VERSION 5.7 ;
BUSBITCHARS "[]" ;
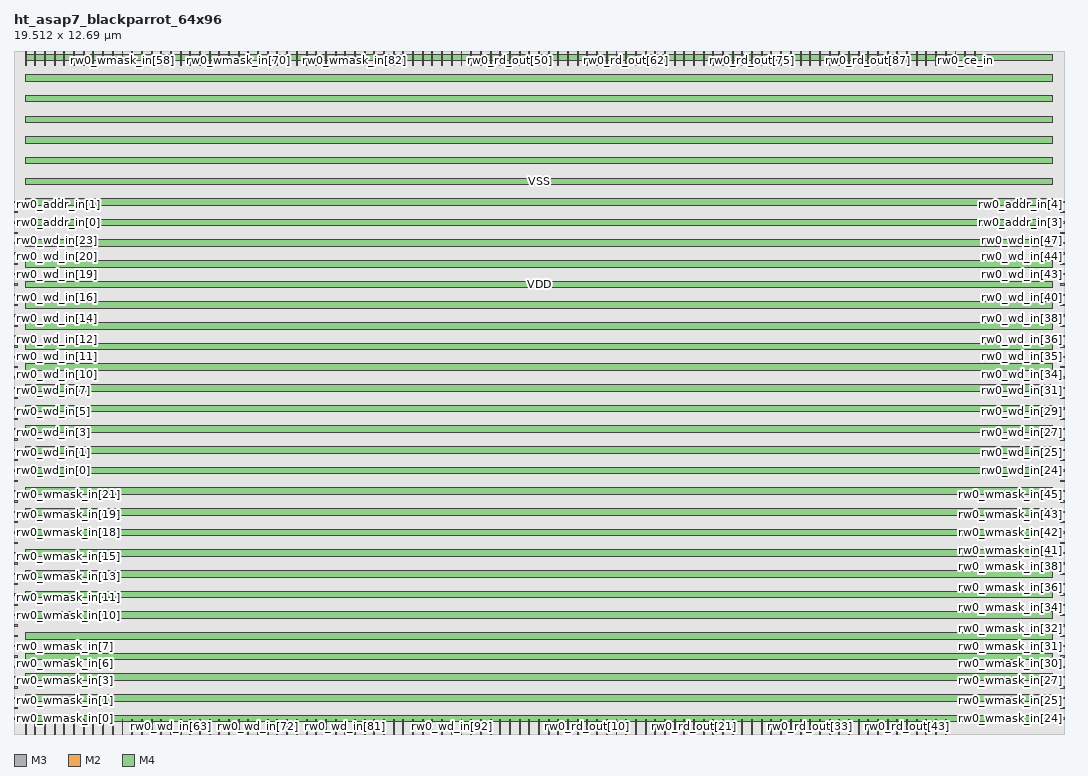
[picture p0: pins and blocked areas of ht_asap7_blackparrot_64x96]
MACRO ht_asap7_blackparrot_64x96
  FOREIGN ht_asap7_blackparrot_64x96 0 0 ;
  SYMMETRY X Y R90 ;
  SIZE 19.512 BY 12.690 ;
  CLASS BLOCK ;
  PIN rw0_wmask_in[0]
    DIRECTION INPUT ;
    USE SIGNAL ;
    SHAPE ABUTMENT ;
    PORT
      LAYER M3 ;
      RECT 0.000 0.276 0.072 0.300 ;
    END
  END rw0_wmask_in[0]
  PIN rw0_wmask_in[1]
    DIRECTION INPUT ;
    USE SIGNAL ;
    SHAPE ABUTMENT ;
    PORT
      LAYER M3 ;
      RECT 0.000 0.468 0.072 0.492 ;
    END
  END rw0_wmask_in[1]
  PIN rw0_wmask_in[2]
    DIRECTION INPUT ;
    USE SIGNAL ;
    SHAPE ABUTMENT ;
    PORT
      LAYER M3 ;
      RECT 0.000 0.660 0.072 0.684 ;
    END
  END rw0_wmask_in[2]
  PIN rw0_wmask_in[3]
    DIRECTION INPUT ;
    USE SIGNAL ;
    SHAPE ABUTMENT ;
    PORT
      LAYER M3 ;
      RECT 0.000 0.852 0.072 0.876 ;
    END
  END rw0_wmask_in[3]
  PIN rw0_wmask_in[4]
    DIRECTION INPUT ;
    USE SIGNAL ;
    SHAPE ABUTMENT ;
    PORT
      LAYER M3 ;
      RECT 0.000 1.044 0.072 1.068 ;
    END
  END rw0_wmask_in[4]
  PIN rw0_wmask_in[5]
    DIRECTION INPUT ;
    USE SIGNAL ;
    SHAPE ABUTMENT ;
    PORT
      LAYER M3 ;
      RECT 0.000 1.236 0.072 1.260 ;
    END
  END rw0_wmask_in[5]
  PIN rw0_wmask_in[6]
    DIRECTION INPUT ;
    USE SIGNAL ;
    SHAPE ABUTMENT ;
    PORT
      LAYER M3 ;
      RECT 0.000 1.428 0.072 1.452 ;
    END
  END rw0_wmask_in[6]
  PIN rw0_wmask_in[7]
    DIRECTION INPUT ;
    USE SIGNAL ;
    SHAPE ABUTMENT ;
    PORT
      LAYER M3 ;
      RECT 0.000 1.620 0.072 1.644 ;
    END
  END rw0_wmask_in[7]
  PIN rw0_wmask_in[8]
    DIRECTION INPUT ;
    USE SIGNAL ;
    SHAPE ABUTMENT ;
    PORT
      LAYER M3 ;
      RECT 0.000 1.812 0.072 1.836 ;
    END
  END rw0_wmask_in[8]
  PIN rw0_wmask_in[9]
    DIRECTION INPUT ;
    USE SIGNAL ;
    SHAPE ABUTMENT ;
    PORT
      LAYER M3 ;
      RECT 0.000 2.004 0.072 2.028 ;
    END
  END rw0_wmask_in[9]
  PIN rw0_wmask_in[10]
    DIRECTION INPUT ;
    USE SIGNAL ;
    SHAPE ABUTMENT ;
    PORT
      LAYER M3 ;
      RECT 0.000 2.196 0.072 2.220 ;
    END
  END rw0_wmask_in[10]
  PIN rw0_wmask_in[11]
    DIRECTION INPUT ;
    USE SIGNAL ;
    SHAPE ABUTMENT ;
    PORT
      LAYER M3 ;
      RECT 0.000 2.388 0.072 2.412 ;
    END
  END rw0_wmask_in[11]
  PIN rw0_wmask_in[12]
    DIRECTION INPUT ;
    USE SIGNAL ;
    SHAPE ABUTMENT ;
    PORT
      LAYER M3 ;
      RECT 0.000 2.580 0.072 2.604 ;
    END
  END rw0_wmask_in[12]
  PIN rw0_wmask_in[13]
    DIRECTION INPUT ;
    USE SIGNAL ;
    SHAPE ABUTMENT ;
    PORT
      LAYER M3 ;
      RECT 0.000 2.772 0.072 2.796 ;
    END
  END rw0_wmask_in[13]
  PIN rw0_wmask_in[14]
    DIRECTION INPUT ;
    USE SIGNAL ;
    SHAPE ABUTMENT ;
    PORT
      LAYER M3 ;
      RECT 0.000 2.964 0.072 2.988 ;
    END
  END rw0_wmask_in[14]
  PIN rw0_wmask_in[15]
    DIRECTION INPUT ;
    USE SIGNAL ;
    SHAPE ABUTMENT ;
    PORT
      LAYER M3 ;
      RECT 0.000 3.156 0.072 3.180 ;
    END
  END rw0_wmask_in[15]
  PIN rw0_wmask_in[16]
    DIRECTION INPUT ;
    USE SIGNAL ;
    SHAPE ABUTMENT ;
    PORT
      LAYER M3 ;
      RECT 0.000 3.348 0.072 3.372 ;
    END
  END rw0_wmask_in[16]
  PIN rw0_wmask_in[17]
    DIRECTION INPUT ;
    USE SIGNAL ;
    SHAPE ABUTMENT ;
    PORT
      LAYER M3 ;
      RECT 0.000 3.540 0.072 3.564 ;
    END
  END rw0_wmask_in[17]
  PIN rw0_wmask_in[18]
    DIRECTION INPUT ;
    USE SIGNAL ;
    SHAPE ABUTMENT ;
    PORT
      LAYER M3 ;
      RECT 0.000 3.732 0.072 3.756 ;
    END
  END rw0_wmask_in[18]
  PIN rw0_wmask_in[19]
    DIRECTION INPUT ;
    USE SIGNAL ;
    SHAPE ABUTMENT ;
    PORT
      LAYER M3 ;
      RECT 0.000 3.924 0.072 3.948 ;
    END
  END rw0_wmask_in[19]
  PIN rw0_wmask_in[20]
    DIRECTION INPUT ;
    USE SIGNAL ;
    SHAPE ABUTMENT ;
    PORT
      LAYER M3 ;
      RECT 0.000 4.116 0.072 4.140 ;
    END
  END rw0_wmask_in[20]
  PIN rw0_wmask_in[21]
    DIRECTION INPUT ;
    USE SIGNAL ;
    SHAPE ABUTMENT ;
    PORT
      LAYER M3 ;
      RECT 0.000 4.308 0.072 4.332 ;
    END
  END rw0_wmask_in[21]
  PIN rw0_wmask_in[22]
    DIRECTION INPUT ;
    USE SIGNAL ;
    SHAPE ABUTMENT ;
    PORT
      LAYER M3 ;
      RECT 0.000 4.500 0.072 4.524 ;
    END
  END rw0_wmask_in[22]
  PIN rw0_wmask_in[23]
    DIRECTION INPUT ;
    USE SIGNAL ;
    SHAPE ABUTMENT ;
    PORT
      LAYER M3 ;
      RECT 0.000 4.692 0.072 4.716 ;
    END
  END rw0_wmask_in[23]
  PIN rw0_wmask_in[24]
    DIRECTION INPUT ;
    USE SIGNAL ;
    SHAPE ABUTMENT ;
    PORT
      LAYER M3 ;
      RECT 19.440 0.276 19.512 0.300 ;
    END
  END rw0_wmask_in[24]
  PIN rw0_wmask_in[25]
    DIRECTION INPUT ;
    USE SIGNAL ;
    SHAPE ABUTMENT ;
    PORT
      LAYER M3 ;
      RECT 19.440 0.468 19.512 0.492 ;
    END
  END rw0_wmask_in[25]
  PIN rw0_wmask_in[26]
    DIRECTION INPUT ;
    USE SIGNAL ;
    SHAPE ABUTMENT ;
    PORT
      LAYER M3 ;
      RECT 19.440 0.660 19.512 0.684 ;
    END
  END rw0_wmask_in[26]
  PIN rw0_wmask_in[27]
    DIRECTION INPUT ;
    USE SIGNAL ;
    SHAPE ABUTMENT ;
    PORT
      LAYER M3 ;
      RECT 19.440 0.852 19.512 0.876 ;
    END
  END rw0_wmask_in[27]
  PIN rw0_wmask_in[28]
    DIRECTION INPUT ;
    USE SIGNAL ;
    SHAPE ABUTMENT ;
    PORT
      LAYER M3 ;
      RECT 19.440 1.044 19.512 1.068 ;
    END
  END rw0_wmask_in[28]
  PIN rw0_wmask_in[29]
    DIRECTION INPUT ;
    USE SIGNAL ;
    SHAPE ABUTMENT ;
    PORT
      LAYER M3 ;
      RECT 19.440 1.236 19.512 1.260 ;
    END
  END rw0_wmask_in[29]
  PIN rw0_wmask_in[30]
    DIRECTION INPUT ;
    USE SIGNAL ;
    SHAPE ABUTMENT ;
    PORT
      LAYER M3 ;
      RECT 19.440 1.428 19.512 1.452 ;
    END
  END rw0_wmask_in[30]
  PIN rw0_wmask_in[31]
    DIRECTION INPUT ;
    USE SIGNAL ;
    SHAPE ABUTMENT ;
    PORT
      LAYER M3 ;
      RECT 19.440 1.620 19.512 1.644 ;
    END
  END rw0_wmask_in[31]
  PIN rw0_wmask_in[32]
    DIRECTION INPUT ;
    USE SIGNAL ;
    SHAPE ABUTMENT ;
    PORT
      LAYER M3 ;
      RECT 19.440 1.812 19.512 1.836 ;
    END
  END rw0_wmask_in[32]
  PIN rw0_wmask_in[33]
    DIRECTION INPUT ;
    USE SIGNAL ;
    SHAPE ABUTMENT ;
    PORT
      LAYER M3 ;
      RECT 19.440 2.004 19.512 2.028 ;
    END
  END rw0_wmask_in[33]
  PIN rw0_wmask_in[34]
    DIRECTION INPUT ;
    USE SIGNAL ;
    SHAPE ABUTMENT ;
    PORT
      LAYER M3 ;
      RECT 19.440 2.196 19.512 2.220 ;
    END
  END rw0_wmask_in[34]
  PIN rw0_wmask_in[35]
    DIRECTION INPUT ;
    USE SIGNAL ;
    SHAPE ABUTMENT ;
    PORT
      LAYER M3 ;
      RECT 19.440 2.388 19.512 2.412 ;
    END
  END rw0_wmask_in[35]
  PIN rw0_wmask_in[36]
    DIRECTION INPUT ;
    USE SIGNAL ;
    SHAPE ABUTMENT ;
    PORT
      LAYER M3 ;
      RECT 19.440 2.580 19.512 2.604 ;
    END
  END rw0_wmask_in[36]
  PIN rw0_wmask_in[37]
    DIRECTION INPUT ;
    USE SIGNAL ;
    SHAPE ABUTMENT ;
    PORT
      LAYER M3 ;
      RECT 19.440 2.772 19.512 2.796 ;
    END
  END rw0_wmask_in[37]
  PIN rw0_wmask_in[38]
    DIRECTION INPUT ;
    USE SIGNAL ;
    SHAPE ABUTMENT ;
    PORT
      LAYER M3 ;
      RECT 19.440 2.964 19.512 2.988 ;
    END
  END rw0_wmask_in[38]
  PIN rw0_wmask_in[39]
    DIRECTION INPUT ;
    USE SIGNAL ;
    SHAPE ABUTMENT ;
    PORT
      LAYER M3 ;
      RECT 19.440 3.156 19.512 3.180 ;
    END
  END rw0_wmask_in[39]
  PIN rw0_wmask_in[40]
    DIRECTION INPUT ;
    USE SIGNAL ;
    SHAPE ABUTMENT ;
    PORT
      LAYER M3 ;
      RECT 19.440 3.348 19.512 3.372 ;
    END
  END rw0_wmask_in[40]
  PIN rw0_wmask_in[41]
    DIRECTION INPUT ;
    USE SIGNAL ;
    SHAPE ABUTMENT ;
    PORT
      LAYER M3 ;
      RECT 19.440 3.540 19.512 3.564 ;
    END
  END rw0_wmask_in[41]
  PIN rw0_wmask_in[42]
    DIRECTION INPUT ;
    USE SIGNAL ;
    SHAPE ABUTMENT ;
    PORT
      LAYER M3 ;
      RECT 19.440 3.732 19.512 3.756 ;
    END
  END rw0_wmask_in[42]
  PIN rw0_wmask_in[43]
    DIRECTION INPUT ;
    USE SIGNAL ;
    SHAPE ABUTMENT ;
    PORT
      LAYER M3 ;
      RECT 19.440 3.924 19.512 3.948 ;
    END
  END rw0_wmask_in[43]
  PIN rw0_wmask_in[44]
    DIRECTION INPUT ;
    USE SIGNAL ;
    SHAPE ABUTMENT ;
    PORT
      LAYER M3 ;
      RECT 19.440 4.116 19.512 4.140 ;
    END
  END rw0_wmask_in[44]
  PIN rw0_wmask_in[45]
    DIRECTION INPUT ;
    USE SIGNAL ;
    SHAPE ABUTMENT ;
    PORT
      LAYER M3 ;
      RECT 19.440 4.308 19.512 4.332 ;
    END
  END rw0_wmask_in[45]
  PIN rw0_wmask_in[46]
    DIRECTION INPUT ;
    USE SIGNAL ;
    SHAPE ABUTMENT ;
    PORT
      LAYER M3 ;
      RECT 19.440 4.500 19.512 4.524 ;
    END
  END rw0_wmask_in[46]
  PIN rw0_wmask_in[47]
    DIRECTION INPUT ;
    USE SIGNAL ;
    SHAPE ABUTMENT ;
    PORT
      LAYER M3 ;
      RECT 19.440 4.692 19.512 4.716 ;
    END
  END rw0_wmask_in[47]
  PIN rw0_wmask_in[48]
    DIRECTION INPUT ;
    USE SIGNAL ;
    SHAPE ABUTMENT ;
    PORT
      LAYER M2 ;
      RECT 0.207 12.420 0.225 12.690 ;
    END
  END rw0_wmask_in[48]
  PIN rw0_wmask_in[49]
    DIRECTION INPUT ;
    USE SIGNAL ;
    SHAPE ABUTMENT ;
    PORT
      LAYER M2 ;
      RECT 0.387 12.420 0.405 12.690 ;
    END
  END rw0_wmask_in[49]
  PIN rw0_wmask_in[50]
    DIRECTION INPUT ;
    USE SIGNAL ;
    SHAPE ABUTMENT ;
    PORT
      LAYER M2 ;
      RECT 0.567 12.420 0.585 12.690 ;
    END
  END rw0_wmask_in[50]
  PIN rw0_wmask_in[51]
    DIRECTION INPUT ;
    USE SIGNAL ;
    SHAPE ABUTMENT ;
    PORT
      LAYER M2 ;
      RECT 0.747 12.420 0.765 12.690 ;
    END
  END rw0_wmask_in[51]
  PIN rw0_wmask_in[52]
    DIRECTION INPUT ;
    USE SIGNAL ;
    SHAPE ABUTMENT ;
    PORT
      LAYER M2 ;
      RECT 0.927 12.420 0.945 12.690 ;
    END
  END rw0_wmask_in[52]
  PIN rw0_wmask_in[53]
    DIRECTION INPUT ;
    USE SIGNAL ;
    SHAPE ABUTMENT ;
    PORT
      LAYER M2 ;
      RECT 1.107 12.420 1.125 12.690 ;
    END
  END rw0_wmask_in[53]
  PIN rw0_wmask_in[54]
    DIRECTION INPUT ;
    USE SIGNAL ;
    SHAPE ABUTMENT ;
    PORT
      LAYER M2 ;
      RECT 1.287 12.420 1.305 12.690 ;
    END
  END rw0_wmask_in[54]
  PIN rw0_wmask_in[55]
    DIRECTION INPUT ;
    USE SIGNAL ;
    SHAPE ABUTMENT ;
    PORT
      LAYER M2 ;
      RECT 1.467 12.420 1.485 12.690 ;
    END
  END rw0_wmask_in[55]
  PIN rw0_wmask_in[56]
    DIRECTION INPUT ;
    USE SIGNAL ;
    SHAPE ABUTMENT ;
    PORT
      LAYER M2 ;
      RECT 1.647 12.420 1.665 12.690 ;
    END
  END rw0_wmask_in[56]
  PIN rw0_wmask_in[57]
    DIRECTION INPUT ;
    USE SIGNAL ;
    SHAPE ABUTMENT ;
    PORT
      LAYER M2 ;
      RECT 1.827 12.420 1.845 12.690 ;
    END
  END rw0_wmask_in[57]
  PIN rw0_wmask_in[58]
    DIRECTION INPUT ;
    USE SIGNAL ;
    SHAPE ABUTMENT ;
    PORT
      LAYER M2 ;
      RECT 2.007 12.420 2.025 12.690 ;
    END
  END rw0_wmask_in[58]
  PIN rw0_wmask_in[59]
    DIRECTION INPUT ;
    USE SIGNAL ;
    SHAPE ABUTMENT ;
    PORT
      LAYER M2 ;
      RECT 2.187 12.420 2.205 12.690 ;
    END
  END rw0_wmask_in[59]
  PIN rw0_wmask_in[60]
    DIRECTION INPUT ;
    USE SIGNAL ;
    SHAPE ABUTMENT ;
    PORT
      LAYER M2 ;
      RECT 2.367 12.420 2.385 12.690 ;
    END
  END rw0_wmask_in[60]
  PIN rw0_wmask_in[61]
    DIRECTION INPUT ;
    USE SIGNAL ;
    SHAPE ABUTMENT ;
    PORT
      LAYER M2 ;
      RECT 2.547 12.420 2.565 12.690 ;
    END
  END rw0_wmask_in[61]
  PIN rw0_wmask_in[62]
    DIRECTION INPUT ;
    USE SIGNAL ;
    SHAPE ABUTMENT ;
    PORT
      LAYER M2 ;
      RECT 2.727 12.420 2.745 12.690 ;
    END
  END rw0_wmask_in[62]
  PIN rw0_wmask_in[63]
    DIRECTION INPUT ;
    USE SIGNAL ;
    SHAPE ABUTMENT ;
    PORT
      LAYER M2 ;
      RECT 2.907 12.420 2.925 12.690 ;
    END
  END rw0_wmask_in[63]
  PIN rw0_wmask_in[64]
    DIRECTION INPUT ;
    USE SIGNAL ;
    SHAPE ABUTMENT ;
    PORT
      LAYER M2 ;
      RECT 3.087 12.420 3.105 12.690 ;
    END
  END rw0_wmask_in[64]
  PIN rw0_wmask_in[65]
    DIRECTION INPUT ;
    USE SIGNAL ;
    SHAPE ABUTMENT ;
    PORT
      LAYER M2 ;
      RECT 3.267 12.420 3.285 12.690 ;
    END
  END rw0_wmask_in[65]
  PIN rw0_wmask_in[66]
    DIRECTION INPUT ;
    USE SIGNAL ;
    SHAPE ABUTMENT ;
    PORT
      LAYER M2 ;
      RECT 3.447 12.420 3.465 12.690 ;
    END
  END rw0_wmask_in[66]
  PIN rw0_wmask_in[67]
    DIRECTION INPUT ;
    USE SIGNAL ;
    SHAPE ABUTMENT ;
    PORT
      LAYER M2 ;
      RECT 3.627 12.420 3.645 12.690 ;
    END
  END rw0_wmask_in[67]
  PIN rw0_wmask_in[68]
    DIRECTION INPUT ;
    USE SIGNAL ;
    SHAPE ABUTMENT ;
    PORT
      LAYER M2 ;
      RECT 3.807 12.420 3.825 12.690 ;
    END
  END rw0_wmask_in[68]
  PIN rw0_wmask_in[69]
    DIRECTION INPUT ;
    USE SIGNAL ;
    SHAPE ABUTMENT ;
    PORT
      LAYER M2 ;
      RECT 3.987 12.420 4.005 12.690 ;
    END
  END rw0_wmask_in[69]
  PIN rw0_wmask_in[70]
    DIRECTION INPUT ;
    USE SIGNAL ;
    SHAPE ABUTMENT ;
    PORT
      LAYER M2 ;
      RECT 4.167 12.420 4.185 12.690 ;
    END
  END rw0_wmask_in[70]
  PIN rw0_wmask_in[71]
    DIRECTION INPUT ;
    USE SIGNAL ;
    SHAPE ABUTMENT ;
    PORT
      LAYER M2 ;
      RECT 4.347 12.420 4.365 12.690 ;
    END
  END rw0_wmask_in[71]
  PIN rw0_wmask_in[72]
    DIRECTION INPUT ;
    USE SIGNAL ;
    SHAPE ABUTMENT ;
    PORT
      LAYER M2 ;
      RECT 4.527 12.420 4.545 12.690 ;
    END
  END rw0_wmask_in[72]
  PIN rw0_wmask_in[73]
    DIRECTION INPUT ;
    USE SIGNAL ;
    SHAPE ABUTMENT ;
    PORT
      LAYER M2 ;
      RECT 4.707 12.420 4.725 12.690 ;
    END
  END rw0_wmask_in[73]
  PIN rw0_wmask_in[74]
    DIRECTION INPUT ;
    USE SIGNAL ;
    SHAPE ABUTMENT ;
    PORT
      LAYER M2 ;
      RECT 4.887 12.420 4.905 12.690 ;
    END
  END rw0_wmask_in[74]
  PIN rw0_wmask_in[75]
    DIRECTION INPUT ;
    USE SIGNAL ;
    SHAPE ABUTMENT ;
    PORT
      LAYER M2 ;
      RECT 5.067 12.420 5.085 12.690 ;
    END
  END rw0_wmask_in[75]
  PIN rw0_wmask_in[76]
    DIRECTION INPUT ;
    USE SIGNAL ;
    SHAPE ABUTMENT ;
    PORT
      LAYER M2 ;
      RECT 5.247 12.420 5.265 12.690 ;
    END
  END rw0_wmask_in[76]
  PIN rw0_wmask_in[77]
    DIRECTION INPUT ;
    USE SIGNAL ;
    SHAPE ABUTMENT ;
    PORT
      LAYER M2 ;
      RECT 5.427 12.420 5.445 12.690 ;
    END
  END rw0_wmask_in[77]
  PIN rw0_wmask_in[78]
    DIRECTION INPUT ;
    USE SIGNAL ;
    SHAPE ABUTMENT ;
    PORT
      LAYER M2 ;
      RECT 5.607 12.420 5.625 12.690 ;
    END
  END rw0_wmask_in[78]
  PIN rw0_wmask_in[79]
    DIRECTION INPUT ;
    USE SIGNAL ;
    SHAPE ABUTMENT ;
    PORT
      LAYER M2 ;
      RECT 5.787 12.420 5.805 12.690 ;
    END
  END rw0_wmask_in[79]
  PIN rw0_wmask_in[80]
    DIRECTION INPUT ;
    USE SIGNAL ;
    SHAPE ABUTMENT ;
    PORT
      LAYER M2 ;
      RECT 5.967 12.420 5.985 12.690 ;
    END
  END rw0_wmask_in[80]
  PIN rw0_wmask_in[81]
    DIRECTION INPUT ;
    USE SIGNAL ;
    SHAPE ABUTMENT ;
    PORT
      LAYER M2 ;
      RECT 6.147 12.420 6.165 12.690 ;
    END
  END rw0_wmask_in[81]
  PIN rw0_wmask_in[82]
    DIRECTION INPUT ;
    USE SIGNAL ;
    SHAPE ABUTMENT ;
    PORT
      LAYER M2 ;
      RECT 6.327 12.420 6.345 12.690 ;
    END
  END rw0_wmask_in[82]
  PIN rw0_wmask_in[83]
    DIRECTION INPUT ;
    USE SIGNAL ;
    SHAPE ABUTMENT ;
    PORT
      LAYER M2 ;
      RECT 6.507 12.420 6.525 12.690 ;
    END
  END rw0_wmask_in[83]
  PIN rw0_wmask_in[84]
    DIRECTION INPUT ;
    USE SIGNAL ;
    SHAPE ABUTMENT ;
    PORT
      LAYER M2 ;
      RECT 6.687 12.420 6.705 12.690 ;
    END
  END rw0_wmask_in[84]
  PIN rw0_wmask_in[85]
    DIRECTION INPUT ;
    USE SIGNAL ;
    SHAPE ABUTMENT ;
    PORT
      LAYER M2 ;
      RECT 6.867 12.420 6.885 12.690 ;
    END
  END rw0_wmask_in[85]
  PIN rw0_wmask_in[86]
    DIRECTION INPUT ;
    USE SIGNAL ;
    SHAPE ABUTMENT ;
    PORT
      LAYER M2 ;
      RECT 7.047 12.420 7.065 12.690 ;
    END
  END rw0_wmask_in[86]
  PIN rw0_wmask_in[87]
    DIRECTION INPUT ;
    USE SIGNAL ;
    SHAPE ABUTMENT ;
    PORT
      LAYER M2 ;
      RECT 7.227 12.420 7.245 12.690 ;
    END
  END rw0_wmask_in[87]
  PIN rw0_wmask_in[88]
    DIRECTION INPUT ;
    USE SIGNAL ;
    SHAPE ABUTMENT ;
    PORT
      LAYER M2 ;
      RECT 7.407 12.420 7.425 12.690 ;
    END
  END rw0_wmask_in[88]
  PIN rw0_wmask_in[89]
    DIRECTION INPUT ;
    USE SIGNAL ;
    SHAPE ABUTMENT ;
    PORT
      LAYER M2 ;
      RECT 7.587 12.420 7.605 12.690 ;
    END
  END rw0_wmask_in[89]
  PIN rw0_wmask_in[90]
    DIRECTION INPUT ;
    USE SIGNAL ;
    SHAPE ABUTMENT ;
    PORT
      LAYER M2 ;
      RECT 7.767 12.420 7.785 12.690 ;
    END
  END rw0_wmask_in[90]
  PIN rw0_wmask_in[91]
    DIRECTION INPUT ;
    USE SIGNAL ;
    SHAPE ABUTMENT ;
    PORT
      LAYER M2 ;
      RECT 7.947 12.420 7.965 12.690 ;
    END
  END rw0_wmask_in[91]
  PIN rw0_wmask_in[92]
    DIRECTION INPUT ;
    USE SIGNAL ;
    SHAPE ABUTMENT ;
    PORT
      LAYER M2 ;
      RECT 8.127 12.420 8.145 12.690 ;
    END
  END rw0_wmask_in[92]
  PIN rw0_wmask_in[93]
    DIRECTION INPUT ;
    USE SIGNAL ;
    SHAPE ABUTMENT ;
    PORT
      LAYER M2 ;
      RECT 8.307 12.420 8.325 12.690 ;
    END
  END rw0_wmask_in[93]
  PIN rw0_wmask_in[94]
    DIRECTION INPUT ;
    USE SIGNAL ;
    SHAPE ABUTMENT ;
    PORT
      LAYER M2 ;
      RECT 8.487 12.420 8.505 12.690 ;
    END
  END rw0_wmask_in[94]
  PIN rw0_wmask_in[95]
    DIRECTION INPUT ;
    USE SIGNAL ;
    SHAPE ABUTMENT ;
    PORT
      LAYER M2 ;
      RECT 8.667 12.420 8.685 12.690 ;
    END
  END rw0_wmask_in[95]
  PIN rw0_wd_in[0]
    DIRECTION INPUT ;
    USE SIGNAL ;
    SHAPE ABUTMENT ;
    PORT
      LAYER M3 ;
      RECT 0.000 4.884 0.072 4.908 ;
    END
  END rw0_wd_in[0]
  PIN rw0_wd_in[1]
    DIRECTION INPUT ;
    USE SIGNAL ;
    SHAPE ABUTMENT ;
    PORT
      LAYER M3 ;
      RECT 0.000 5.076 0.072 5.100 ;
    END
  END rw0_wd_in[1]
  PIN rw0_wd_in[2]
    DIRECTION INPUT ;
    USE SIGNAL ;
    SHAPE ABUTMENT ;
    PORT
      LAYER M3 ;
      RECT 0.000 5.268 0.072 5.292 ;
    END
  END rw0_wd_in[2]
  PIN rw0_wd_in[3]
    DIRECTION INPUT ;
    USE SIGNAL ;
    SHAPE ABUTMENT ;
    PORT
      LAYER M3 ;
      RECT 0.000 5.460 0.072 5.484 ;
    END
  END rw0_wd_in[3]
  PIN rw0_wd_in[4]
    DIRECTION INPUT ;
    USE SIGNAL ;
    SHAPE ABUTMENT ;
    PORT
      LAYER M3 ;
      RECT 0.000 5.652 0.072 5.676 ;
    END
  END rw0_wd_in[4]
  PIN rw0_wd_in[5]
    DIRECTION INPUT ;
    USE SIGNAL ;
    SHAPE ABUTMENT ;
    PORT
      LAYER M3 ;
      RECT 0.000 5.844 0.072 5.868 ;
    END
  END rw0_wd_in[5]
  PIN rw0_wd_in[6]
    DIRECTION INPUT ;
    USE SIGNAL ;
    SHAPE ABUTMENT ;
    PORT
      LAYER M3 ;
      RECT 0.000 6.036 0.072 6.060 ;
    END
  END rw0_wd_in[6]
  PIN rw0_wd_in[7]
    DIRECTION INPUT ;
    USE SIGNAL ;
    SHAPE ABUTMENT ;
    PORT
      LAYER M3 ;
      RECT 0.000 6.228 0.072 6.252 ;
    END
  END rw0_wd_in[7]
  PIN rw0_wd_in[8]
    DIRECTION INPUT ;
    USE SIGNAL ;
    SHAPE ABUTMENT ;
    PORT
      LAYER M3 ;
      RECT 0.000 6.420 0.072 6.444 ;
    END
  END rw0_wd_in[8]
  PIN rw0_wd_in[9]
    DIRECTION INPUT ;
    USE SIGNAL ;
    SHAPE ABUTMENT ;
    PORT
      LAYER M3 ;
      RECT 0.000 6.612 0.072 6.636 ;
    END
  END rw0_wd_in[9]
  PIN rw0_wd_in[10]
    DIRECTION INPUT ;
    USE SIGNAL ;
    SHAPE ABUTMENT ;
    PORT
      LAYER M3 ;
      RECT 0.000 6.804 0.072 6.828 ;
    END
  END rw0_wd_in[10]
  PIN rw0_wd_in[11]
    DIRECTION INPUT ;
    USE SIGNAL ;
    SHAPE ABUTMENT ;
    PORT
      LAYER M3 ;
      RECT 0.000 6.996 0.072 7.020 ;
    END
  END rw0_wd_in[11]
  PIN rw0_wd_in[12]
    DIRECTION INPUT ;
    USE SIGNAL ;
    SHAPE ABUTMENT ;
    PORT
      LAYER M3 ;
      RECT 0.000 7.188 0.072 7.212 ;
    END
  END rw0_wd_in[12]
  PIN rw0_wd_in[13]
    DIRECTION INPUT ;
    USE SIGNAL ;
    SHAPE ABUTMENT ;
    PORT
      LAYER M3 ;
      RECT 0.000 7.380 0.072 7.404 ;
    END
  END rw0_wd_in[13]
  PIN rw0_wd_in[14]
    DIRECTION INPUT ;
    USE SIGNAL ;
    SHAPE ABUTMENT ;
    PORT
      LAYER M3 ;
      RECT 0.000 7.572 0.072 7.596 ;
    END
  END rw0_wd_in[14]
  PIN rw0_wd_in[15]
    DIRECTION INPUT ;
    USE SIGNAL ;
    SHAPE ABUTMENT ;
    PORT
      LAYER M3 ;
      RECT 0.000 7.764 0.072 7.788 ;
    END
  END rw0_wd_in[15]
  PIN rw0_wd_in[16]
    DIRECTION INPUT ;
    USE SIGNAL ;
    SHAPE ABUTMENT ;
    PORT
      LAYER M3 ;
      RECT 0.000 7.956 0.072 7.980 ;
    END
  END rw0_wd_in[16]
  PIN rw0_wd_in[17]
    DIRECTION INPUT ;
    USE SIGNAL ;
    SHAPE ABUTMENT ;
    PORT
      LAYER M3 ;
      RECT 0.000 8.148 0.072 8.172 ;
    END
  END rw0_wd_in[17]
  PIN rw0_wd_in[18]
    DIRECTION INPUT ;
    USE SIGNAL ;
    SHAPE ABUTMENT ;
    PORT
      LAYER M3 ;
      RECT 0.000 8.340 0.072 8.364 ;
    END
  END rw0_wd_in[18]
  PIN rw0_wd_in[19]
    DIRECTION INPUT ;
    USE SIGNAL ;
    SHAPE ABUTMENT ;
    PORT
      LAYER M3 ;
      RECT 0.000 8.532 0.072 8.556 ;
    END
  END rw0_wd_in[19]
  PIN rw0_wd_in[20]
    DIRECTION INPUT ;
    USE SIGNAL ;
    SHAPE ABUTMENT ;
    PORT
      LAYER M3 ;
      RECT 0.000 8.724 0.072 8.748 ;
    END
  END rw0_wd_in[20]
  PIN rw0_wd_in[21]
    DIRECTION INPUT ;
    USE SIGNAL ;
    SHAPE ABUTMENT ;
    PORT
      LAYER M3 ;
      RECT 0.000 8.916 0.072 8.940 ;
    END
  END rw0_wd_in[21]
  PIN rw0_wd_in[22]
    DIRECTION INPUT ;
    USE SIGNAL ;
    SHAPE ABUTMENT ;
    PORT
      LAYER M3 ;
      RECT 0.000 9.108 0.072 9.132 ;
    END
  END rw0_wd_in[22]
  PIN rw0_wd_in[23]
    DIRECTION INPUT ;
    USE SIGNAL ;
    SHAPE ABUTMENT ;
    PORT
      LAYER M3 ;
      RECT 0.000 9.300 0.072 9.324 ;
    END
  END rw0_wd_in[23]
  PIN rw0_wd_in[24]
    DIRECTION INPUT ;
    USE SIGNAL ;
    SHAPE ABUTMENT ;
    PORT
      LAYER M3 ;
      RECT 19.440 4.884 19.512 4.908 ;
    END
  END rw0_wd_in[24]
  PIN rw0_wd_in[25]
    DIRECTION INPUT ;
    USE SIGNAL ;
    SHAPE ABUTMENT ;
    PORT
      LAYER M3 ;
      RECT 19.440 5.076 19.512 5.100 ;
    END
  END rw0_wd_in[25]
  PIN rw0_wd_in[26]
    DIRECTION INPUT ;
    USE SIGNAL ;
    SHAPE ABUTMENT ;
    PORT
      LAYER M3 ;
      RECT 19.440 5.268 19.512 5.292 ;
    END
  END rw0_wd_in[26]
  PIN rw0_wd_in[27]
    DIRECTION INPUT ;
    USE SIGNAL ;
    SHAPE ABUTMENT ;
    PORT
      LAYER M3 ;
      RECT 19.440 5.460 19.512 5.484 ;
    END
  END rw0_wd_in[27]
  PIN rw0_wd_in[28]
    DIRECTION INPUT ;
    USE SIGNAL ;
    SHAPE ABUTMENT ;
    PORT
      LAYER M3 ;
      RECT 19.440 5.652 19.512 5.676 ;
    END
  END rw0_wd_in[28]
  PIN rw0_wd_in[29]
    DIRECTION INPUT ;
    USE SIGNAL ;
    SHAPE ABUTMENT ;
    PORT
      LAYER M3 ;
      RECT 19.440 5.844 19.512 5.868 ;
    END
  END rw0_wd_in[29]
  PIN rw0_wd_in[30]
    DIRECTION INPUT ;
    USE SIGNAL ;
    SHAPE ABUTMENT ;
    PORT
      LAYER M3 ;
      RECT 19.440 6.036 19.512 6.060 ;
    END
  END rw0_wd_in[30]
  PIN rw0_wd_in[31]
    DIRECTION INPUT ;
    USE SIGNAL ;
    SHAPE ABUTMENT ;
    PORT
      LAYER M3 ;
      RECT 19.440 6.228 19.512 6.252 ;
    END
  END rw0_wd_in[31]
  PIN rw0_wd_in[32]
    DIRECTION INPUT ;
    USE SIGNAL ;
    SHAPE ABUTMENT ;
    PORT
      LAYER M3 ;
      RECT 19.440 6.420 19.512 6.444 ;
    END
  END rw0_wd_in[32]
  PIN rw0_wd_in[33]
    DIRECTION INPUT ;
    USE SIGNAL ;
    SHAPE ABUTMENT ;
    PORT
      LAYER M3 ;
      RECT 19.440 6.612 19.512 6.636 ;
    END
  END rw0_wd_in[33]
  PIN rw0_wd_in[34]
    DIRECTION INPUT ;
    USE SIGNAL ;
    SHAPE ABUTMENT ;
    PORT
      LAYER M3 ;
      RECT 19.440 6.804 19.512 6.828 ;
    END
  END rw0_wd_in[34]
  PIN rw0_wd_in[35]
    DIRECTION INPUT ;
    USE SIGNAL ;
    SHAPE ABUTMENT ;
    PORT
      LAYER M3 ;
      RECT 19.440 6.996 19.512 7.020 ;
    END
  END rw0_wd_in[35]
  PIN rw0_wd_in[36]
    DIRECTION INPUT ;
    USE SIGNAL ;
    SHAPE ABUTMENT ;
    PORT
      LAYER M3 ;
      RECT 19.440 7.188 19.512 7.212 ;
    END
  END rw0_wd_in[36]
  PIN rw0_wd_in[37]
    DIRECTION INPUT ;
    USE SIGNAL ;
    SHAPE ABUTMENT ;
    PORT
      LAYER M3 ;
      RECT 19.440 7.380 19.512 7.404 ;
    END
  END rw0_wd_in[37]
  PIN rw0_wd_in[38]
    DIRECTION INPUT ;
    USE SIGNAL ;
    SHAPE ABUTMENT ;
    PORT
      LAYER M3 ;
      RECT 19.440 7.572 19.512 7.596 ;
    END
  END rw0_wd_in[38]
  PIN rw0_wd_in[39]
    DIRECTION INPUT ;
    USE SIGNAL ;
    SHAPE ABUTMENT ;
    PORT
      LAYER M3 ;
      RECT 19.440 7.764 19.512 7.788 ;
    END
  END rw0_wd_in[39]
  PIN rw0_wd_in[40]
    DIRECTION INPUT ;
    USE SIGNAL ;
    SHAPE ABUTMENT ;
    PORT
      LAYER M3 ;
      RECT 19.440 7.956 19.512 7.980 ;
    END
  END rw0_wd_in[40]
  PIN rw0_wd_in[41]
    DIRECTION INPUT ;
    USE SIGNAL ;
    SHAPE ABUTMENT ;
    PORT
      LAYER M3 ;
      RECT 19.440 8.148 19.512 8.172 ;
    END
  END rw0_wd_in[41]
  PIN rw0_wd_in[42]
    DIRECTION INPUT ;
    USE SIGNAL ;
    SHAPE ABUTMENT ;
    PORT
      LAYER M3 ;
      RECT 19.440 8.340 19.512 8.364 ;
    END
  END rw0_wd_in[42]
  PIN rw0_wd_in[43]
    DIRECTION INPUT ;
    USE SIGNAL ;
    SHAPE ABUTMENT ;
    PORT
      LAYER M3 ;
      RECT 19.440 8.532 19.512 8.556 ;
    END
  END rw0_wd_in[43]
  PIN rw0_wd_in[44]
    DIRECTION INPUT ;
    USE SIGNAL ;
    SHAPE ABUTMENT ;
    PORT
      LAYER M3 ;
      RECT 19.440 8.724 19.512 8.748 ;
    END
  END rw0_wd_in[44]
  PIN rw0_wd_in[45]
    DIRECTION INPUT ;
    USE SIGNAL ;
    SHAPE ABUTMENT ;
    PORT
      LAYER M3 ;
      RECT 19.440 8.916 19.512 8.940 ;
    END
  END rw0_wd_in[45]
  PIN rw0_wd_in[46]
    DIRECTION INPUT ;
    USE SIGNAL ;
    SHAPE ABUTMENT ;
    PORT
      LAYER M3 ;
      RECT 19.440 9.108 19.512 9.132 ;
    END
  END rw0_wd_in[46]
  PIN rw0_wd_in[47]
    DIRECTION INPUT ;
    USE SIGNAL ;
    SHAPE ABUTMENT ;
    PORT
      LAYER M3 ;
      RECT 19.440 9.300 19.512 9.324 ;
    END
  END rw0_wd_in[47]
  PIN rw0_wd_in[48]
    DIRECTION INPUT ;
    USE SIGNAL ;
    SHAPE ABUTMENT ;
    PORT
      LAYER M2 ;
      RECT 0.207 0.000 0.225 0.270 ;
    END
  END rw0_wd_in[48]
  PIN rw0_wd_in[49]
    DIRECTION INPUT ;
    USE SIGNAL ;
    SHAPE ABUTMENT ;
    PORT
      LAYER M2 ;
      RECT 0.387 0.000 0.405 0.270 ;
    END
  END rw0_wd_in[49]
  PIN rw0_wd_in[50]
    DIRECTION INPUT ;
    USE SIGNAL ;
    SHAPE ABUTMENT ;
    PORT
      LAYER M2 ;
      RECT 0.567 0.000 0.585 0.270 ;
    END
  END rw0_wd_in[50]
  PIN rw0_wd_in[51]
    DIRECTION INPUT ;
    USE SIGNAL ;
    SHAPE ABUTMENT ;
    PORT
      LAYER M2 ;
      RECT 0.747 0.000 0.765 0.270 ;
    END
  END rw0_wd_in[51]
  PIN rw0_wd_in[52]
    DIRECTION INPUT ;
    USE SIGNAL ;
    SHAPE ABUTMENT ;
    PORT
      LAYER M2 ;
      RECT 0.927 0.000 0.945 0.270 ;
    END
  END rw0_wd_in[52]
  PIN rw0_wd_in[53]
    DIRECTION INPUT ;
    USE SIGNAL ;
    SHAPE ABUTMENT ;
    PORT
      LAYER M2 ;
      RECT 1.107 0.000 1.125 0.270 ;
    END
  END rw0_wd_in[53]
  PIN rw0_wd_in[54]
    DIRECTION INPUT ;
    USE SIGNAL ;
    SHAPE ABUTMENT ;
    PORT
      LAYER M2 ;
      RECT 1.287 0.000 1.305 0.270 ;
    END
  END rw0_wd_in[54]
  PIN rw0_wd_in[55]
    DIRECTION INPUT ;
    USE SIGNAL ;
    SHAPE ABUTMENT ;
    PORT
      LAYER M2 ;
      RECT 1.467 0.000 1.485 0.270 ;
    END
  END rw0_wd_in[55]
  PIN rw0_wd_in[56]
    DIRECTION INPUT ;
    USE SIGNAL ;
    SHAPE ABUTMENT ;
    PORT
      LAYER M2 ;
      RECT 1.647 0.000 1.665 0.270 ;
    END
  END rw0_wd_in[56]
  PIN rw0_wd_in[57]
    DIRECTION INPUT ;
    USE SIGNAL ;
    SHAPE ABUTMENT ;
    PORT
      LAYER M2 ;
      RECT 1.827 0.000 1.845 0.270 ;
    END
  END rw0_wd_in[57]
  PIN rw0_wd_in[58]
    DIRECTION INPUT ;
    USE SIGNAL ;
    SHAPE ABUTMENT ;
    PORT
      LAYER M2 ;
      RECT 2.007 0.000 2.025 0.270 ;
    END
  END rw0_wd_in[58]
  PIN rw0_wd_in[59]
    DIRECTION INPUT ;
    USE SIGNAL ;
    SHAPE ABUTMENT ;
    PORT
      LAYER M2 ;
      RECT 2.187 0.000 2.205 0.270 ;
    END
  END rw0_wd_in[59]
  PIN rw0_wd_in[60]
    DIRECTION INPUT ;
    USE SIGNAL ;
    SHAPE ABUTMENT ;
    PORT
      LAYER M2 ;
      RECT 2.367 0.000 2.385 0.270 ;
    END
  END rw0_wd_in[60]
  PIN rw0_wd_in[61]
    DIRECTION INPUT ;
    USE SIGNAL ;
    SHAPE ABUTMENT ;
    PORT
      LAYER M2 ;
      RECT 2.547 0.000 2.565 0.270 ;
    END
  END rw0_wd_in[61]
  PIN rw0_wd_in[62]
    DIRECTION INPUT ;
    USE SIGNAL ;
    SHAPE ABUTMENT ;
    PORT
      LAYER M2 ;
      RECT 2.727 0.000 2.745 0.270 ;
    END
  END rw0_wd_in[62]
  PIN rw0_wd_in[63]
    DIRECTION INPUT ;
    USE SIGNAL ;
    SHAPE ABUTMENT ;
    PORT
      LAYER M2 ;
      RECT 2.907 0.000 2.925 0.270 ;
    END
  END rw0_wd_in[63]
  PIN rw0_wd_in[64]
    DIRECTION INPUT ;
    USE SIGNAL ;
    SHAPE ABUTMENT ;
    PORT
      LAYER M2 ;
      RECT 3.087 0.000 3.105 0.270 ;
    END
  END rw0_wd_in[64]
  PIN rw0_wd_in[65]
    DIRECTION INPUT ;
    USE SIGNAL ;
    SHAPE ABUTMENT ;
    PORT
      LAYER M2 ;
      RECT 3.267 0.000 3.285 0.270 ;
    END
  END rw0_wd_in[65]
  PIN rw0_wd_in[66]
    DIRECTION INPUT ;
    USE SIGNAL ;
    SHAPE ABUTMENT ;
    PORT
      LAYER M2 ;
      RECT 3.447 0.000 3.465 0.270 ;
    END
  END rw0_wd_in[66]
  PIN rw0_wd_in[67]
    DIRECTION INPUT ;
    USE SIGNAL ;
    SHAPE ABUTMENT ;
    PORT
      LAYER M2 ;
      RECT 3.627 0.000 3.645 0.270 ;
    END
  END rw0_wd_in[67]
  PIN rw0_wd_in[68]
    DIRECTION INPUT ;
    USE SIGNAL ;
    SHAPE ABUTMENT ;
    PORT
      LAYER M2 ;
      RECT 3.807 0.000 3.825 0.270 ;
    END
  END rw0_wd_in[68]
  PIN rw0_wd_in[69]
    DIRECTION INPUT ;
    USE SIGNAL ;
    SHAPE ABUTMENT ;
    PORT
      LAYER M2 ;
      RECT 3.987 0.000 4.005 0.270 ;
    END
  END rw0_wd_in[69]
  PIN rw0_wd_in[70]
    DIRECTION INPUT ;
    USE SIGNAL ;
    SHAPE ABUTMENT ;
    PORT
      LAYER M2 ;
      RECT 4.167 0.000 4.185 0.270 ;
    END
  END rw0_wd_in[70]
  PIN rw0_wd_in[71]
    DIRECTION INPUT ;
    USE SIGNAL ;
    SHAPE ABUTMENT ;
    PORT
      LAYER M2 ;
      RECT 4.347 0.000 4.365 0.270 ;
    END
  END rw0_wd_in[71]
  PIN rw0_wd_in[72]
    DIRECTION INPUT ;
    USE SIGNAL ;
    SHAPE ABUTMENT ;
    PORT
      LAYER M2 ;
      RECT 4.527 0.000 4.545 0.270 ;
    END
  END rw0_wd_in[72]
  PIN rw0_wd_in[73]
    DIRECTION INPUT ;
    USE SIGNAL ;
    SHAPE ABUTMENT ;
    PORT
      LAYER M2 ;
      RECT 4.707 0.000 4.725 0.270 ;
    END
  END rw0_wd_in[73]
  PIN rw0_wd_in[74]
    DIRECTION INPUT ;
    USE SIGNAL ;
    SHAPE ABUTMENT ;
    PORT
      LAYER M2 ;
      RECT 4.887 0.000 4.905 0.270 ;
    END
  END rw0_wd_in[74]
  PIN rw0_wd_in[75]
    DIRECTION INPUT ;
    USE SIGNAL ;
    SHAPE ABUTMENT ;
    PORT
      LAYER M2 ;
      RECT 5.067 0.000 5.085 0.270 ;
    END
  END rw0_wd_in[75]
  PIN rw0_wd_in[76]
    DIRECTION INPUT ;
    USE SIGNAL ;
    SHAPE ABUTMENT ;
    PORT
      LAYER M2 ;
      RECT 5.247 0.000 5.265 0.270 ;
    END
  END rw0_wd_in[76]
  PIN rw0_wd_in[77]
    DIRECTION INPUT ;
    USE SIGNAL ;
    SHAPE ABUTMENT ;
    PORT
      LAYER M2 ;
      RECT 5.427 0.000 5.445 0.270 ;
    END
  END rw0_wd_in[77]
  PIN rw0_wd_in[78]
    DIRECTION INPUT ;
    USE SIGNAL ;
    SHAPE ABUTMENT ;
    PORT
      LAYER M2 ;
      RECT 5.607 0.000 5.625 0.270 ;
    END
  END rw0_wd_in[78]
  PIN rw0_wd_in[79]
    DIRECTION INPUT ;
    USE SIGNAL ;
    SHAPE ABUTMENT ;
    PORT
      LAYER M2 ;
      RECT 5.787 0.000 5.805 0.270 ;
    END
  END rw0_wd_in[79]
  PIN rw0_wd_in[80]
    DIRECTION INPUT ;
    USE SIGNAL ;
    SHAPE ABUTMENT ;
    PORT
      LAYER M2 ;
      RECT 5.967 0.000 5.985 0.270 ;
    END
  END rw0_wd_in[80]
  PIN rw0_wd_in[81]
    DIRECTION INPUT ;
    USE SIGNAL ;
    SHAPE ABUTMENT ;
    PORT
      LAYER M2 ;
      RECT 6.147 0.000 6.165 0.270 ;
    END
  END rw0_wd_in[81]
  PIN rw0_wd_in[82]
    DIRECTION INPUT ;
    USE SIGNAL ;
    SHAPE ABUTMENT ;
    PORT
      LAYER M2 ;
      RECT 6.327 0.000 6.345 0.270 ;
    END
  END rw0_wd_in[82]
  PIN rw0_wd_in[83]
    DIRECTION INPUT ;
    USE SIGNAL ;
    SHAPE ABUTMENT ;
    PORT
      LAYER M2 ;
      RECT 6.507 0.000 6.525 0.270 ;
    END
  END rw0_wd_in[83]
  PIN rw0_wd_in[84]
    DIRECTION INPUT ;
    USE SIGNAL ;
    SHAPE ABUTMENT ;
    PORT
      LAYER M2 ;
      RECT 6.687 0.000 6.705 0.270 ;
    END
  END rw0_wd_in[84]
  PIN rw0_wd_in[85]
    DIRECTION INPUT ;
    USE SIGNAL ;
    SHAPE ABUTMENT ;
    PORT
      LAYER M2 ;
      RECT 6.867 0.000 6.885 0.270 ;
    END
  END rw0_wd_in[85]
  PIN rw0_wd_in[86]
    DIRECTION INPUT ;
    USE SIGNAL ;
    SHAPE ABUTMENT ;
    PORT
      LAYER M2 ;
      RECT 7.047 0.000 7.065 0.270 ;
    END
  END rw0_wd_in[86]
  PIN rw0_wd_in[87]
    DIRECTION INPUT ;
    USE SIGNAL ;
    SHAPE ABUTMENT ;
    PORT
      LAYER M2 ;
      RECT 7.227 0.000 7.245 0.270 ;
    END
  END rw0_wd_in[87]
  PIN rw0_wd_in[88]
    DIRECTION INPUT ;
    USE SIGNAL ;
    SHAPE ABUTMENT ;
    PORT
      LAYER M2 ;
      RECT 7.407 0.000 7.425 0.270 ;
    END
  END rw0_wd_in[88]
  PIN rw0_wd_in[89]
    DIRECTION INPUT ;
    USE SIGNAL ;
    SHAPE ABUTMENT ;
    PORT
      LAYER M2 ;
      RECT 7.587 0.000 7.605 0.270 ;
    END
  END rw0_wd_in[89]
  PIN rw0_wd_in[90]
    DIRECTION INPUT ;
    USE SIGNAL ;
    SHAPE ABUTMENT ;
    PORT
      LAYER M2 ;
      RECT 7.767 0.000 7.785 0.270 ;
    END
  END rw0_wd_in[90]
  PIN rw0_wd_in[91]
    DIRECTION INPUT ;
    USE SIGNAL ;
    SHAPE ABUTMENT ;
    PORT
      LAYER M2 ;
      RECT 7.947 0.000 7.965 0.270 ;
    END
  END rw0_wd_in[91]
  PIN rw0_wd_in[92]
    DIRECTION INPUT ;
    USE SIGNAL ;
    SHAPE ABUTMENT ;
    PORT
      LAYER M2 ;
      RECT 8.127 0.000 8.145 0.270 ;
    END
  END rw0_wd_in[92]
  PIN rw0_wd_in[93]
    DIRECTION INPUT ;
    USE SIGNAL ;
    SHAPE ABUTMENT ;
    PORT
      LAYER M2 ;
      RECT 8.307 0.000 8.325 0.270 ;
    END
  END rw0_wd_in[93]
  PIN rw0_wd_in[94]
    DIRECTION INPUT ;
    USE SIGNAL ;
    SHAPE ABUTMENT ;
    PORT
      LAYER M2 ;
      RECT 8.487 0.000 8.505 0.270 ;
    END
  END rw0_wd_in[94]
  PIN rw0_wd_in[95]
    DIRECTION INPUT ;
    USE SIGNAL ;
    SHAPE ABUTMENT ;
    PORT
      LAYER M2 ;
      RECT 8.667 0.000 8.685 0.270 ;
    END
  END rw0_wd_in[95]
  PIN rw0_rd_out[0]
    DIRECTION OUTPUT ;
    USE SIGNAL ;
    SHAPE ABUTMENT ;
    PORT
      LAYER M2 ;
      RECT 8.847 0.000 8.865 0.270 ;
    END
  END rw0_rd_out[0]
  PIN rw0_rd_out[1]
    DIRECTION OUTPUT ;
    USE SIGNAL ;
    SHAPE ABUTMENT ;
    PORT
      LAYER M2 ;
      RECT 9.027 0.000 9.045 0.270 ;
    END
  END rw0_rd_out[1]
  PIN rw0_rd_out[2]
    DIRECTION OUTPUT ;
    USE SIGNAL ;
    SHAPE ABUTMENT ;
    PORT
      LAYER M2 ;
      RECT 9.207 0.000 9.225 0.270 ;
    END
  END rw0_rd_out[2]
  PIN rw0_rd_out[3]
    DIRECTION OUTPUT ;
    USE SIGNAL ;
    SHAPE ABUTMENT ;
    PORT
      LAYER M2 ;
      RECT 9.387 0.000 9.405 0.270 ;
    END
  END rw0_rd_out[3]
  PIN rw0_rd_out[4]
    DIRECTION OUTPUT ;
    USE SIGNAL ;
    SHAPE ABUTMENT ;
    PORT
      LAYER M2 ;
      RECT 9.567 0.000 9.585 0.270 ;
    END
  END rw0_rd_out[4]
  PIN rw0_rd_out[5]
    DIRECTION OUTPUT ;
    USE SIGNAL ;
    SHAPE ABUTMENT ;
    PORT
      LAYER M2 ;
      RECT 9.747 0.000 9.765 0.270 ;
    END
  END rw0_rd_out[5]
  PIN rw0_rd_out[6]
    DIRECTION OUTPUT ;
    USE SIGNAL ;
    SHAPE ABUTMENT ;
    PORT
      LAYER M2 ;
      RECT 9.927 0.000 9.945 0.270 ;
    END
  END rw0_rd_out[6]
  PIN rw0_rd_out[7]
    DIRECTION OUTPUT ;
    USE SIGNAL ;
    SHAPE ABUTMENT ;
    PORT
      LAYER M2 ;
      RECT 10.107 0.000 10.125 0.270 ;
    END
  END rw0_rd_out[7]
  PIN rw0_rd_out[8]
    DIRECTION OUTPUT ;
    USE SIGNAL ;
    SHAPE ABUTMENT ;
    PORT
      LAYER M2 ;
      RECT 10.287 0.000 10.305 0.270 ;
    END
  END rw0_rd_out[8]
  PIN rw0_rd_out[9]
    DIRECTION OUTPUT ;
    USE SIGNAL ;
    SHAPE ABUTMENT ;
    PORT
      LAYER M2 ;
      RECT 10.467 0.000 10.485 0.270 ;
    END
  END rw0_rd_out[9]
  PIN rw0_rd_out[10]
    DIRECTION OUTPUT ;
    USE SIGNAL ;
    SHAPE ABUTMENT ;
    PORT
      LAYER M2 ;
      RECT 10.647 0.000 10.665 0.270 ;
    END
  END rw0_rd_out[10]
  PIN rw0_rd_out[11]
    DIRECTION OUTPUT ;
    USE SIGNAL ;
    SHAPE ABUTMENT ;
    PORT
      LAYER M2 ;
      RECT 10.827 0.000 10.845 0.270 ;
    END
  END rw0_rd_out[11]
  PIN rw0_rd_out[12]
    DIRECTION OUTPUT ;
    USE SIGNAL ;
    SHAPE ABUTMENT ;
    PORT
      LAYER M2 ;
      RECT 11.007 0.000 11.025 0.270 ;
    END
  END rw0_rd_out[12]
  PIN rw0_rd_out[13]
    DIRECTION OUTPUT ;
    USE SIGNAL ;
    SHAPE ABUTMENT ;
    PORT
      LAYER M2 ;
      RECT 11.187 0.000 11.205 0.270 ;
    END
  END rw0_rd_out[13]
  PIN rw0_rd_out[14]
    DIRECTION OUTPUT ;
    USE SIGNAL ;
    SHAPE ABUTMENT ;
    PORT
      LAYER M2 ;
      RECT 11.367 0.000 11.385 0.270 ;
    END
  END rw0_rd_out[14]
  PIN rw0_rd_out[15]
    DIRECTION OUTPUT ;
    USE SIGNAL ;
    SHAPE ABUTMENT ;
    PORT
      LAYER M2 ;
      RECT 11.547 0.000 11.565 0.270 ;
    END
  END rw0_rd_out[15]
  PIN rw0_rd_out[16]
    DIRECTION OUTPUT ;
    USE SIGNAL ;
    SHAPE ABUTMENT ;
    PORT
      LAYER M2 ;
      RECT 11.727 0.000 11.745 0.270 ;
    END
  END rw0_rd_out[16]
  PIN rw0_rd_out[17]
    DIRECTION OUTPUT ;
    USE SIGNAL ;
    SHAPE ABUTMENT ;
    PORT
      LAYER M2 ;
      RECT 11.907 0.000 11.925 0.270 ;
    END
  END rw0_rd_out[17]
  PIN rw0_rd_out[18]
    DIRECTION OUTPUT ;
    USE SIGNAL ;
    SHAPE ABUTMENT ;
    PORT
      LAYER M2 ;
      RECT 12.087 0.000 12.105 0.270 ;
    END
  END rw0_rd_out[18]
  PIN rw0_rd_out[19]
    DIRECTION OUTPUT ;
    USE SIGNAL ;
    SHAPE ABUTMENT ;
    PORT
      LAYER M2 ;
      RECT 12.267 0.000 12.285 0.270 ;
    END
  END rw0_rd_out[19]
  PIN rw0_rd_out[20]
    DIRECTION OUTPUT ;
    USE SIGNAL ;
    SHAPE ABUTMENT ;
    PORT
      LAYER M2 ;
      RECT 12.447 0.000 12.465 0.270 ;
    END
  END rw0_rd_out[20]
  PIN rw0_rd_out[21]
    DIRECTION OUTPUT ;
    USE SIGNAL ;
    SHAPE ABUTMENT ;
    PORT
      LAYER M2 ;
      RECT 12.627 0.000 12.645 0.270 ;
    END
  END rw0_rd_out[21]
  PIN rw0_rd_out[22]
    DIRECTION OUTPUT ;
    USE SIGNAL ;
    SHAPE ABUTMENT ;
    PORT
      LAYER M2 ;
      RECT 12.807 0.000 12.825 0.270 ;
    END
  END rw0_rd_out[22]
  PIN rw0_rd_out[23]
    DIRECTION OUTPUT ;
    USE SIGNAL ;
    SHAPE ABUTMENT ;
    PORT
      LAYER M2 ;
      RECT 12.987 0.000 13.005 0.270 ;
    END
  END rw0_rd_out[23]
  PIN rw0_rd_out[24]
    DIRECTION OUTPUT ;
    USE SIGNAL ;
    SHAPE ABUTMENT ;
    PORT
      LAYER M2 ;
      RECT 13.167 0.000 13.185 0.270 ;
    END
  END rw0_rd_out[24]
  PIN rw0_rd_out[25]
    DIRECTION OUTPUT ;
    USE SIGNAL ;
    SHAPE ABUTMENT ;
    PORT
      LAYER M2 ;
      RECT 13.347 0.000 13.365 0.270 ;
    END
  END rw0_rd_out[25]
  PIN rw0_rd_out[26]
    DIRECTION OUTPUT ;
    USE SIGNAL ;
    SHAPE ABUTMENT ;
    PORT
      LAYER M2 ;
      RECT 13.527 0.000 13.545 0.270 ;
    END
  END rw0_rd_out[26]
  PIN rw0_rd_out[27]
    DIRECTION OUTPUT ;
    USE SIGNAL ;
    SHAPE ABUTMENT ;
    PORT
      LAYER M2 ;
      RECT 13.707 0.000 13.725 0.270 ;
    END
  END rw0_rd_out[27]
  PIN rw0_rd_out[28]
    DIRECTION OUTPUT ;
    USE SIGNAL ;
    SHAPE ABUTMENT ;
    PORT
      LAYER M2 ;
      RECT 13.887 0.000 13.905 0.270 ;
    END
  END rw0_rd_out[28]
  PIN rw0_rd_out[29]
    DIRECTION OUTPUT ;
    USE SIGNAL ;
    SHAPE ABUTMENT ;
    PORT
      LAYER M2 ;
      RECT 14.067 0.000 14.085 0.270 ;
    END
  END rw0_rd_out[29]
  PIN rw0_rd_out[30]
    DIRECTION OUTPUT ;
    USE SIGNAL ;
    SHAPE ABUTMENT ;
    PORT
      LAYER M2 ;
      RECT 14.247 0.000 14.265 0.270 ;
    END
  END rw0_rd_out[30]
  PIN rw0_rd_out[31]
    DIRECTION OUTPUT ;
    USE SIGNAL ;
    SHAPE ABUTMENT ;
    PORT
      LAYER M2 ;
      RECT 14.427 0.000 14.445 0.270 ;
    END
  END rw0_rd_out[31]
  PIN rw0_rd_out[32]
    DIRECTION OUTPUT ;
    USE SIGNAL ;
    SHAPE ABUTMENT ;
    PORT
      LAYER M2 ;
      RECT 14.607 0.000 14.625 0.270 ;
    END
  END rw0_rd_out[32]
  PIN rw0_rd_out[33]
    DIRECTION OUTPUT ;
    USE SIGNAL ;
    SHAPE ABUTMENT ;
    PORT
      LAYER M2 ;
      RECT 14.787 0.000 14.805 0.270 ;
    END
  END rw0_rd_out[33]
  PIN rw0_rd_out[34]
    DIRECTION OUTPUT ;
    USE SIGNAL ;
    SHAPE ABUTMENT ;
    PORT
      LAYER M2 ;
      RECT 14.967 0.000 14.985 0.270 ;
    END
  END rw0_rd_out[34]
  PIN rw0_rd_out[35]
    DIRECTION OUTPUT ;
    USE SIGNAL ;
    SHAPE ABUTMENT ;
    PORT
      LAYER M2 ;
      RECT 15.147 0.000 15.165 0.270 ;
    END
  END rw0_rd_out[35]
  PIN rw0_rd_out[36]
    DIRECTION OUTPUT ;
    USE SIGNAL ;
    SHAPE ABUTMENT ;
    PORT
      LAYER M2 ;
      RECT 15.327 0.000 15.345 0.270 ;
    END
  END rw0_rd_out[36]
  PIN rw0_rd_out[37]
    DIRECTION OUTPUT ;
    USE SIGNAL ;
    SHAPE ABUTMENT ;
    PORT
      LAYER M2 ;
      RECT 15.507 0.000 15.525 0.270 ;
    END
  END rw0_rd_out[37]
  PIN rw0_rd_out[38]
    DIRECTION OUTPUT ;
    USE SIGNAL ;
    SHAPE ABUTMENT ;
    PORT
      LAYER M2 ;
      RECT 15.687 0.000 15.705 0.270 ;
    END
  END rw0_rd_out[38]
  PIN rw0_rd_out[39]
    DIRECTION OUTPUT ;
    USE SIGNAL ;
    SHAPE ABUTMENT ;
    PORT
      LAYER M2 ;
      RECT 15.867 0.000 15.885 0.270 ;
    END
  END rw0_rd_out[39]
  PIN rw0_rd_out[40]
    DIRECTION OUTPUT ;
    USE SIGNAL ;
    SHAPE ABUTMENT ;
    PORT
      LAYER M2 ;
      RECT 16.047 0.000 16.065 0.270 ;
    END
  END rw0_rd_out[40]
  PIN rw0_rd_out[41]
    DIRECTION OUTPUT ;
    USE SIGNAL ;
    SHAPE ABUTMENT ;
    PORT
      LAYER M2 ;
      RECT 16.227 0.000 16.245 0.270 ;
    END
  END rw0_rd_out[41]
  PIN rw0_rd_out[42]
    DIRECTION OUTPUT ;
    USE SIGNAL ;
    SHAPE ABUTMENT ;
    PORT
      LAYER M2 ;
      RECT 16.407 0.000 16.425 0.270 ;
    END
  END rw0_rd_out[42]
  PIN rw0_rd_out[43]
    DIRECTION OUTPUT ;
    USE SIGNAL ;
    SHAPE ABUTMENT ;
    PORT
      LAYER M2 ;
      RECT 16.587 0.000 16.605 0.270 ;
    END
  END rw0_rd_out[43]
  PIN rw0_rd_out[44]
    DIRECTION OUTPUT ;
    USE SIGNAL ;
    SHAPE ABUTMENT ;
    PORT
      LAYER M2 ;
      RECT 16.767 0.000 16.785 0.270 ;
    END
  END rw0_rd_out[44]
  PIN rw0_rd_out[45]
    DIRECTION OUTPUT ;
    USE SIGNAL ;
    SHAPE ABUTMENT ;
    PORT
      LAYER M2 ;
      RECT 16.947 0.000 16.965 0.270 ;
    END
  END rw0_rd_out[45]
  PIN rw0_rd_out[46]
    DIRECTION OUTPUT ;
    USE SIGNAL ;
    SHAPE ABUTMENT ;
    PORT
      LAYER M2 ;
      RECT 17.127 0.000 17.145 0.270 ;
    END
  END rw0_rd_out[46]
  PIN rw0_rd_out[47]
    DIRECTION OUTPUT ;
    USE SIGNAL ;
    SHAPE ABUTMENT ;
    PORT
      LAYER M2 ;
      RECT 17.307 0.000 17.325 0.270 ;
    END
  END rw0_rd_out[47]
  PIN rw0_rd_out[48]
    DIRECTION OUTPUT ;
    USE SIGNAL ;
    SHAPE ABUTMENT ;
    PORT
      LAYER M2 ;
      RECT 8.847 12.420 8.865 12.690 ;
    END
  END rw0_rd_out[48]
  PIN rw0_rd_out[49]
    DIRECTION OUTPUT ;
    USE SIGNAL ;
    SHAPE ABUTMENT ;
    PORT
      LAYER M2 ;
      RECT 9.027 12.420 9.045 12.690 ;
    END
  END rw0_rd_out[49]
  PIN rw0_rd_out[50]
    DIRECTION OUTPUT ;
    USE SIGNAL ;
    SHAPE ABUTMENT ;
    PORT
      LAYER M2 ;
      RECT 9.207 12.420 9.225 12.690 ;
    END
  END rw0_rd_out[50]
  PIN rw0_rd_out[51]
    DIRECTION OUTPUT ;
    USE SIGNAL ;
    SHAPE ABUTMENT ;
    PORT
      LAYER M2 ;
      RECT 9.387 12.420 9.405 12.690 ;
    END
  END rw0_rd_out[51]
  PIN rw0_rd_out[52]
    DIRECTION OUTPUT ;
    USE SIGNAL ;
    SHAPE ABUTMENT ;
    PORT
      LAYER M2 ;
      RECT 9.567 12.420 9.585 12.690 ;
    END
  END rw0_rd_out[52]
  PIN rw0_rd_out[53]
    DIRECTION OUTPUT ;
    USE SIGNAL ;
    SHAPE ABUTMENT ;
    PORT
      LAYER M2 ;
      RECT 9.747 12.420 9.765 12.690 ;
    END
  END rw0_rd_out[53]
  PIN rw0_rd_out[54]
    DIRECTION OUTPUT ;
    USE SIGNAL ;
    SHAPE ABUTMENT ;
    PORT
      LAYER M2 ;
      RECT 9.927 12.420 9.945 12.690 ;
    END
  END rw0_rd_out[54]
  PIN rw0_rd_out[55]
    DIRECTION OUTPUT ;
    USE SIGNAL ;
    SHAPE ABUTMENT ;
    PORT
      LAYER M2 ;
      RECT 10.107 12.420 10.125 12.690 ;
    END
  END rw0_rd_out[55]
  PIN rw0_rd_out[56]
    DIRECTION OUTPUT ;
    USE SIGNAL ;
    SHAPE ABUTMENT ;
    PORT
      LAYER M2 ;
      RECT 10.287 12.420 10.305 12.690 ;
    END
  END rw0_rd_out[56]
  PIN rw0_rd_out[57]
    DIRECTION OUTPUT ;
    USE SIGNAL ;
    SHAPE ABUTMENT ;
    PORT
      LAYER M2 ;
      RECT 10.467 12.420 10.485 12.690 ;
    END
  END rw0_rd_out[57]
  PIN rw0_rd_out[58]
    DIRECTION OUTPUT ;
    USE SIGNAL ;
    SHAPE ABUTMENT ;
    PORT
      LAYER M2 ;
      RECT 10.647 12.420 10.665 12.690 ;
    END
  END rw0_rd_out[58]
  PIN rw0_rd_out[59]
    DIRECTION OUTPUT ;
    USE SIGNAL ;
    SHAPE ABUTMENT ;
    PORT
      LAYER M2 ;
      RECT 10.827 12.420 10.845 12.690 ;
    END
  END rw0_rd_out[59]
  PIN rw0_rd_out[60]
    DIRECTION OUTPUT ;
    USE SIGNAL ;
    SHAPE ABUTMENT ;
    PORT
      LAYER M2 ;
      RECT 11.007 12.420 11.025 12.690 ;
    END
  END rw0_rd_out[60]
  PIN rw0_rd_out[61]
    DIRECTION OUTPUT ;
    USE SIGNAL ;
    SHAPE ABUTMENT ;
    PORT
      LAYER M2 ;
      RECT 11.187 12.420 11.205 12.690 ;
    END
  END rw0_rd_out[61]
  PIN rw0_rd_out[62]
    DIRECTION OUTPUT ;
    USE SIGNAL ;
    SHAPE ABUTMENT ;
    PORT
      LAYER M2 ;
      RECT 11.367 12.420 11.385 12.690 ;
    END
  END rw0_rd_out[62]
  PIN rw0_rd_out[63]
    DIRECTION OUTPUT ;
    USE SIGNAL ;
    SHAPE ABUTMENT ;
    PORT
      LAYER M2 ;
      RECT 11.547 12.420 11.565 12.690 ;
    END
  END rw0_rd_out[63]
  PIN rw0_rd_out[64]
    DIRECTION OUTPUT ;
    USE SIGNAL ;
    SHAPE ABUTMENT ;
    PORT
      LAYER M2 ;
      RECT 11.727 12.420 11.745 12.690 ;
    END
  END rw0_rd_out[64]
  PIN rw0_rd_out[65]
    DIRECTION OUTPUT ;
    USE SIGNAL ;
    SHAPE ABUTMENT ;
    PORT
      LAYER M2 ;
      RECT 11.907 12.420 11.925 12.690 ;
    END
  END rw0_rd_out[65]
  PIN rw0_rd_out[66]
    DIRECTION OUTPUT ;
    USE SIGNAL ;
    SHAPE ABUTMENT ;
    PORT
      LAYER M2 ;
      RECT 12.087 12.420 12.105 12.690 ;
    END
  END rw0_rd_out[66]
  PIN rw0_rd_out[67]
    DIRECTION OUTPUT ;
    USE SIGNAL ;
    SHAPE ABUTMENT ;
    PORT
      LAYER M2 ;
      RECT 12.267 12.420 12.285 12.690 ;
    END
  END rw0_rd_out[67]
  PIN rw0_rd_out[68]
    DIRECTION OUTPUT ;
    USE SIGNAL ;
    SHAPE ABUTMENT ;
    PORT
      LAYER M2 ;
      RECT 12.447 12.420 12.465 12.690 ;
    END
  END rw0_rd_out[68]
  PIN rw0_rd_out[69]
    DIRECTION OUTPUT ;
    USE SIGNAL ;
    SHAPE ABUTMENT ;
    PORT
      LAYER M2 ;
      RECT 12.627 12.420 12.645 12.690 ;
    END
  END rw0_rd_out[69]
  PIN rw0_rd_out[70]
    DIRECTION OUTPUT ;
    USE SIGNAL ;
    SHAPE ABUTMENT ;
    PORT
      LAYER M2 ;
      RECT 12.807 12.420 12.825 12.690 ;
    END
  END rw0_rd_out[70]
  PIN rw0_rd_out[71]
    DIRECTION OUTPUT ;
    USE SIGNAL ;
    SHAPE ABUTMENT ;
    PORT
      LAYER M2 ;
      RECT 12.987 12.420 13.005 12.690 ;
    END
  END rw0_rd_out[71]
  PIN rw0_rd_out[72]
    DIRECTION OUTPUT ;
    USE SIGNAL ;
    SHAPE ABUTMENT ;
    PORT
      LAYER M2 ;
      RECT 13.167 12.420 13.185 12.690 ;
    END
  END rw0_rd_out[72]
  PIN rw0_rd_out[73]
    DIRECTION OUTPUT ;
    USE SIGNAL ;
    SHAPE ABUTMENT ;
    PORT
      LAYER M2 ;
      RECT 13.347 12.420 13.365 12.690 ;
    END
  END rw0_rd_out[73]
  PIN rw0_rd_out[74]
    DIRECTION OUTPUT ;
    USE SIGNAL ;
    SHAPE ABUTMENT ;
    PORT
      LAYER M2 ;
      RECT 13.527 12.420 13.545 12.690 ;
    END
  END rw0_rd_out[74]
  PIN rw0_rd_out[75]
    DIRECTION OUTPUT ;
    USE SIGNAL ;
    SHAPE ABUTMENT ;
    PORT
      LAYER M2 ;
      RECT 13.707 12.420 13.725 12.690 ;
    END
  END rw0_rd_out[75]
  PIN rw0_rd_out[76]
    DIRECTION OUTPUT ;
    USE SIGNAL ;
    SHAPE ABUTMENT ;
    PORT
      LAYER M2 ;
      RECT 13.887 12.420 13.905 12.690 ;
    END
  END rw0_rd_out[76]
  PIN rw0_rd_out[77]
    DIRECTION OUTPUT ;
    USE SIGNAL ;
    SHAPE ABUTMENT ;
    PORT
      LAYER M2 ;
      RECT 14.067 12.420 14.085 12.690 ;
    END
  END rw0_rd_out[77]
  PIN rw0_rd_out[78]
    DIRECTION OUTPUT ;
    USE SIGNAL ;
    SHAPE ABUTMENT ;
    PORT
      LAYER M2 ;
      RECT 14.247 12.420 14.265 12.690 ;
    END
  END rw0_rd_out[78]
  PIN rw0_rd_out[79]
    DIRECTION OUTPUT ;
    USE SIGNAL ;
    SHAPE ABUTMENT ;
    PORT
      LAYER M2 ;
      RECT 14.427 12.420 14.445 12.690 ;
    END
  END rw0_rd_out[79]
  PIN rw0_rd_out[80]
    DIRECTION OUTPUT ;
    USE SIGNAL ;
    SHAPE ABUTMENT ;
    PORT
      LAYER M2 ;
      RECT 14.607 12.420 14.625 12.690 ;
    END
  END rw0_rd_out[80]
  PIN rw0_rd_out[81]
    DIRECTION OUTPUT ;
    USE SIGNAL ;
    SHAPE ABUTMENT ;
    PORT
      LAYER M2 ;
      RECT 14.787 12.420 14.805 12.690 ;
    END
  END rw0_rd_out[81]
  PIN rw0_rd_out[82]
    DIRECTION OUTPUT ;
    USE SIGNAL ;
    SHAPE ABUTMENT ;
    PORT
      LAYER M2 ;
      RECT 14.967 12.420 14.985 12.690 ;
    END
  END rw0_rd_out[82]
  PIN rw0_rd_out[83]
    DIRECTION OUTPUT ;
    USE SIGNAL ;
    SHAPE ABUTMENT ;
    PORT
      LAYER M2 ;
      RECT 15.147 12.420 15.165 12.690 ;
    END
  END rw0_rd_out[83]
  PIN rw0_rd_out[84]
    DIRECTION OUTPUT ;
    USE SIGNAL ;
    SHAPE ABUTMENT ;
    PORT
      LAYER M2 ;
      RECT 15.327 12.420 15.345 12.690 ;
    END
  END rw0_rd_out[84]
  PIN rw0_rd_out[85]
    DIRECTION OUTPUT ;
    USE SIGNAL ;
    SHAPE ABUTMENT ;
    PORT
      LAYER M2 ;
      RECT 15.507 12.420 15.525 12.690 ;
    END
  END rw0_rd_out[85]
  PIN rw0_rd_out[86]
    DIRECTION OUTPUT ;
    USE SIGNAL ;
    SHAPE ABUTMENT ;
    PORT
      LAYER M2 ;
      RECT 15.687 12.420 15.705 12.690 ;
    END
  END rw0_rd_out[86]
  PIN rw0_rd_out[87]
    DIRECTION OUTPUT ;
    USE SIGNAL ;
    SHAPE ABUTMENT ;
    PORT
      LAYER M2 ;
      RECT 15.867 12.420 15.885 12.690 ;
    END
  END rw0_rd_out[87]
  PIN rw0_rd_out[88]
    DIRECTION OUTPUT ;
    USE SIGNAL ;
    SHAPE ABUTMENT ;
    PORT
      LAYER M2 ;
      RECT 16.047 12.420 16.065 12.690 ;
    END
  END rw0_rd_out[88]
  PIN rw0_rd_out[89]
    DIRECTION OUTPUT ;
    USE SIGNAL ;
    SHAPE ABUTMENT ;
    PORT
      LAYER M2 ;
      RECT 16.227 12.420 16.245 12.690 ;
    END
  END rw0_rd_out[89]
  PIN rw0_rd_out[90]
    DIRECTION OUTPUT ;
    USE SIGNAL ;
    SHAPE ABUTMENT ;
    PORT
      LAYER M2 ;
      RECT 16.407 12.420 16.425 12.690 ;
    END
  END rw0_rd_out[90]
  PIN rw0_rd_out[91]
    DIRECTION OUTPUT ;
    USE SIGNAL ;
    SHAPE ABUTMENT ;
    PORT
      LAYER M2 ;
      RECT 16.587 12.420 16.605 12.690 ;
    END
  END rw0_rd_out[91]
  PIN rw0_rd_out[92]
    DIRECTION OUTPUT ;
    USE SIGNAL ;
    SHAPE ABUTMENT ;
    PORT
      LAYER M2 ;
      RECT 16.767 12.420 16.785 12.690 ;
    END
  END rw0_rd_out[92]
  PIN rw0_rd_out[93]
    DIRECTION OUTPUT ;
    USE SIGNAL ;
    SHAPE ABUTMENT ;
    PORT
      LAYER M2 ;
      RECT 16.947 12.420 16.965 12.690 ;
    END
  END rw0_rd_out[93]
  PIN rw0_rd_out[94]
    DIRECTION OUTPUT ;
    USE SIGNAL ;
    SHAPE ABUTMENT ;
    PORT
      LAYER M2 ;
      RECT 17.127 12.420 17.145 12.690 ;
    END
  END rw0_rd_out[94]
  PIN rw0_rd_out[95]
    DIRECTION OUTPUT ;
    USE SIGNAL ;
    SHAPE ABUTMENT ;
    PORT
      LAYER M2 ;
      RECT 17.307 12.420 17.325 12.690 ;
    END
  END rw0_rd_out[95]
  PIN rw0_addr_in[0]
    DIRECTION INPUT ;
    USE SIGNAL ;
    SHAPE ABUTMENT ;
    PORT
      LAYER M3 ;
      RECT 0.000 9.492 0.072 9.516 ;
    END
  END rw0_addr_in[0]
  PIN rw0_addr_in[1]
    DIRECTION INPUT ;
    USE SIGNAL ;
    SHAPE ABUTMENT ;
    PORT
      LAYER M3 ;
      RECT 0.000 9.684 0.072 9.708 ;
    END
  END rw0_addr_in[1]
  PIN rw0_addr_in[2]
    DIRECTION INPUT ;
    USE SIGNAL ;
    SHAPE ABUTMENT ;
    PORT
      LAYER M3 ;
      RECT 0.000 9.876 0.072 9.900 ;
    END
  END rw0_addr_in[2]
  PIN rw0_addr_in[3]
    DIRECTION INPUT ;
    USE SIGNAL ;
    SHAPE ABUTMENT ;
    PORT
      LAYER M3 ;
      RECT 19.440 9.492 19.512 9.516 ;
    END
  END rw0_addr_in[3]
  PIN rw0_addr_in[4]
    DIRECTION INPUT ;
    USE SIGNAL ;
    SHAPE ABUTMENT ;
    PORT
      LAYER M3 ;
      RECT 19.440 9.684 19.512 9.708 ;
    END
  END rw0_addr_in[4]
  PIN rw0_addr_in[5]
    DIRECTION INPUT ;
    USE SIGNAL ;
    SHAPE ABUTMENT ;
    PORT
      LAYER M3 ;
      RECT 19.440 9.876 19.512 9.900 ;
    END
  END rw0_addr_in[5]
  PIN rw0_we_in
    DIRECTION INPUT ;
    USE SIGNAL ;
    SHAPE ABUTMENT ;
    PORT
      LAYER M2 ;
      RECT 17.487 12.420 17.505 12.690 ;
    END
  END rw0_we_in
  PIN rw0_ce_in
    DIRECTION INPUT ;
    USE SIGNAL ;
    SHAPE ABUTMENT ;
    PORT
      LAYER M2 ;
      RECT 17.667 12.420 17.685 12.690 ;
    END
  END rw0_ce_in
  PIN rw0_clk
    DIRECTION INPUT ;
    USE SIGNAL ;
    SHAPE ABUTMENT ;
    PORT
      LAYER M2 ;
      RECT 17.847 12.420 17.865 12.690 ;
    END
  END rw0_clk
  PIN VSS
    DIRECTION INOUT ;
    USE GROUND ;
    PORT
      LAYER M4 ;
      RECT 0.216 0.228 19.296 0.348 ;
      RECT 0.216 0.996 19.296 1.116 ;
      RECT 0.216 1.764 19.296 1.884 ;
      RECT 0.216 2.532 19.296 2.652 ;
      RECT 0.216 3.300 19.296 3.420 ;
      RECT 0.216 4.068 19.296 4.188 ;
      RECT 0.216 4.836 19.296 4.956 ;
      RECT 0.216 5.604 19.296 5.724 ;
      RECT 0.216 6.372 19.296 6.492 ;
      RECT 0.216 7.140 19.296 7.260 ;
      RECT 0.216 7.908 19.296 8.028 ;
      RECT 0.216 8.676 19.296 8.796 ;
      RECT 0.216 9.444 19.296 9.564 ;
      RECT 0.216 10.212 19.296 10.332 ;
      RECT 0.216 10.980 19.296 11.100 ;
      RECT 0.216 11.748 19.296 11.868 ;
      RECT 0.216 12.516 19.296 12.636 ;
    END
  END VSS
  PIN VDD
    DIRECTION INOUT ;
    USE POWER ;
    PORT
      LAYER M4 ;
      RECT 0.216 0.612 19.296 0.732 ;
      RECT 0.216 1.380 19.296 1.500 ;
      RECT 0.216 2.148 19.296 2.268 ;
      RECT 0.216 2.916 19.296 3.036 ;
      RECT 0.216 3.684 19.296 3.804 ;
      RECT 0.216 4.452 19.296 4.572 ;
      RECT 0.216 5.220 19.296 5.340 ;
      RECT 0.216 5.988 19.296 6.108 ;
      RECT 0.216 6.756 19.296 6.876 ;
      RECT 0.216 7.524 19.296 7.644 ;
      RECT 0.216 8.292 19.296 8.412 ;
      RECT 0.216 9.060 19.296 9.180 ;
      RECT 0.216 9.828 19.296 9.948 ;
      RECT 0.216 10.596 19.296 10.716 ;
      RECT 0.216 11.364 19.296 11.484 ;
      RECT 0.216 12.132 19.296 12.252 ;
    END
  END VDD
  OBS
    LAYER M1 ;
    RECT 0 0 19.512 12.690 ;
    LAYER M2 ;
    RECT 0 0 19.512 12.690 ;
    LAYER M3 ;
    RECT 0 0 19.512 12.690 ;
    LAYER M4 ;
    RECT 0 0 19.512 12.690 ;
  END
END ht_asap7_blackparrot_64x96

END LIBRARY
